VERSION 5.7 ;
  NOWIREEXTENSIONATPIN ON ;
  DIVIDERCHAR "/" ;
  BUSBITCHARS "[]" ;
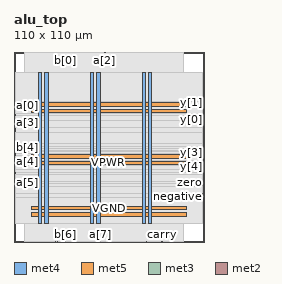
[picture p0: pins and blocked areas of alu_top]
MACRO alu_top
  CLASS BLOCK ;
  FOREIGN alu_top ;
  ORIGIN 0.000 0.000 ;
  SIZE 110.000 BY 110.000 ;
  PIN VGND
    DIRECTION INOUT ;
    USE GROUND ;
    PORT
      LAYER met4 ;
        RECT 17.820 10.640 19.820 98.160 ;
    END
    PORT
      LAYER met4 ;
        RECT 47.820 10.640 49.820 98.160 ;
    END
    PORT
      LAYER met4 ;
        RECT 77.820 10.640 79.820 98.160 ;
    END
    PORT
      LAYER met5 ;
        RECT 10.120 18.580 99.820 20.580 ;
    END
    PORT
      LAYER met5 ;
        RECT 10.120 48.580 99.820 50.580 ;
    END
    PORT
      LAYER met5 ;
        RECT 10.120 78.580 99.820 80.580 ;
    END
  END VGND
  PIN VPWR
    DIRECTION INOUT ;
    USE POWER ;
    PORT
      LAYER met4 ;
        RECT 14.120 10.640 16.120 98.160 ;
    END
    PORT
      LAYER met4 ;
        RECT 44.120 10.640 46.120 98.160 ;
    END
    PORT
      LAYER met4 ;
        RECT 74.120 10.640 76.120 98.160 ;
    END
    PORT
      LAYER met5 ;
        RECT 10.120 14.880 99.820 16.880 ;
    END
    PORT
      LAYER met5 ;
        RECT 10.120 44.880 99.820 46.880 ;
    END
    PORT
      LAYER met5 ;
        RECT 10.120 74.880 99.820 76.880 ;
    END
  END VPWR
  PIN a[0]
    DIRECTION INPUT ;
    USE SIGNAL ;
    ANTENNAGATEAREA 0.213000 ;
    PORT
      LAYER met3 ;
        RECT 0.000 78.920 0.600 79.520 ;
    END
  END a[0]
  PIN a[1]
    DIRECTION INPUT ;
    USE SIGNAL ;
    ANTENNAGATEAREA 0.213000 ;
    PORT
      LAYER met2 ;
        RECT 40.570 109.720 40.850 110.000 ;
    END
  END a[1]
  PIN a[2]
    DIRECTION INPUT ;
    USE SIGNAL ;
    ANTENNAGATEAREA 0.213000 ;
    PORT
      LAYER met2 ;
        RECT 52.530 109.720 52.810 110.000 ;
    END
  END a[2]
  PIN a[3]
    DIRECTION INPUT ;
    USE SIGNAL ;
    ANTENNAGATEAREA 0.213000 ;
    PORT
      LAYER met3 ;
        RECT 0.000 73.480 0.600 74.080 ;
    END
  END a[3]
  PIN a[4]
    DIRECTION INPUT ;
    USE SIGNAL ;
    ANTENNAGATEAREA 0.213000 ;
    PORT
      LAYER met3 ;
        RECT 0.000 46.280 0.600 46.880 ;
    END
  END a[4]
  PIN a[5]
    DIRECTION INPUT ;
    USE SIGNAL ;
    ANTENNAGATEAREA 0.213000 ;
    PORT
      LAYER met3 ;
        RECT 0.000 34.040 0.600 34.640 ;
    END
  END a[5]
  PIN a[6]
    DIRECTION INPUT ;
    USE SIGNAL ;
    ANTENNAGATEAREA 0.213000 ;
    PORT
      LAYER met2 ;
        RECT 28.610 0.000 28.890 0.280 ;
    END
  END a[6]
  PIN a[7]
    DIRECTION INPUT ;
    USE SIGNAL ;
    ANTENNAGATEAREA 0.213000 ;
    PORT
      LAYER met2 ;
        RECT 49.770 0.000 50.050 0.280 ;
    END
  END a[7]
  PIN b[0]
    DIRECTION INPUT ;
    USE SIGNAL ;
    ANTENNAGATEAREA 0.213000 ;
    PORT
      LAYER met2 ;
        RECT 29.530 109.720 29.810 110.000 ;
    END
  END b[0]
  PIN b[1]
    DIRECTION INPUT ;
    USE SIGNAL ;
    ANTENNAGATEAREA 0.213000 ;
    PORT
      LAYER met2 ;
        RECT 37.810 109.720 38.090 110.000 ;
    END
  END b[1]
  PIN b[2]
    DIRECTION INPUT ;
    USE SIGNAL ;
    ANTENNAGATEAREA 0.213000 ;
    PORT
      LAYER met2 ;
        RECT 55.290 109.720 55.570 110.000 ;
    END
  END b[2]
  PIN b[3]
    DIRECTION INPUT ;
    USE SIGNAL ;
    ANTENNAGATEAREA 0.213000 ;
    PORT
      LAYER met3 ;
        RECT 0.000 65.320 0.600 65.920 ;
    END
  END b[3]
  PIN b[4]
    DIRECTION INPUT ;
    USE SIGNAL ;
    ANTENNAGATEAREA 0.213000 ;
    PORT
      LAYER met3 ;
        RECT 0.000 50.360 0.600 50.960 ;
    END
  END b[4]
  PIN b[5]
    DIRECTION INPUT ;
    USE SIGNAL ;
    ANTENNAGATEAREA 0.213000 ;
    PORT
      LAYER met3 ;
        RECT 0.000 39.480 0.600 40.080 ;
    END
  END b[5]
  PIN b[6]
    DIRECTION INPUT ;
    USE SIGNAL ;
    ANTENNAGATEAREA 0.213000 ;
    PORT
      LAYER met2 ;
        RECT 29.530 0.000 29.810 0.280 ;
    END
  END b[6]
  PIN b[7]
    DIRECTION INPUT ;
    USE SIGNAL ;
    ANTENNAGATEAREA 0.213000 ;
    PORT
      LAYER met2 ;
        RECT 54.370 0.000 54.650 0.280 ;
    END
  END b[7]
  PIN carry
    DIRECTION OUTPUT ;
    USE SIGNAL ;
    ANTENNADIFFAREA 0.702900 ;
    PORT
      LAYER met2 ;
        RECT 85.650 0.000 85.930 0.280 ;
    END
  END carry
  PIN clk
    DIRECTION INPUT ;
    USE SIGNAL ;
    ANTENNAGATEAREA 0.852000 ;
    PORT
      LAYER met2 ;
        RECT 24.930 0.000 25.210 0.280 ;
    END
  END clk
  PIN negative
    DIRECTION OUTPUT ;
    USE SIGNAL ;
    ANTENNADIFFAREA 0.702900 ;
    PORT
      LAYER met3 ;
        RECT 109.400 25.880 110.000 26.480 ;
    END
  END negative
  PIN op[0]
    DIRECTION INPUT ;
    USE SIGNAL ;
    ANTENNAGATEAREA 0.213000 ;
    PORT
      LAYER met3 ;
        RECT 0.000 55.800 0.600 56.400 ;
    END
  END op[0]
  PIN op[1]
    DIRECTION INPUT ;
    USE SIGNAL ;
    ANTENNAGATEAREA 0.213000 ;
    PORT
      LAYER met3 ;
        RECT 0.000 63.960 0.600 64.560 ;
    END
  END op[1]
  PIN op[2]
    DIRECTION INPUT ;
    USE SIGNAL ;
    ANTENNAGATEAREA 0.213000 ;
    PORT
      LAYER met3 ;
        RECT 0.000 53.080 0.600 53.680 ;
    END
  END op[2]
  PIN overflow
    DIRECTION OUTPUT ;
    USE SIGNAL ;
    ANTENNADIFFAREA 0.702900 ;
    PORT
      LAYER met2 ;
        RECT 76.450 0.000 76.730 0.280 ;
    END
  END overflow
  PIN rst_n
    DIRECTION INPUT ;
    USE SIGNAL ;
    ANTENNAGATEAREA 0.213000 ;
    PORT
      LAYER met2 ;
        RECT 24.010 0.000 24.290 0.280 ;
    END
  END rst_n
  PIN y[0]
    DIRECTION OUTPUT ;
    USE SIGNAL ;
    ANTENNADIFFAREA 0.702900 ;
    PORT
      LAYER met3 ;
        RECT 109.400 70.760 110.000 71.360 ;
    END
  END y[0]
  PIN y[1]
    DIRECTION OUTPUT ;
    USE SIGNAL ;
    ANTENNADIFFAREA 0.702900 ;
    PORT
      LAYER met3 ;
        RECT 109.400 80.280 110.000 80.880 ;
    END
  END y[1]
  PIN y[2]
    DIRECTION OUTPUT ;
    USE SIGNAL ;
    ANTENNADIFFAREA 0.702900 ;
    PORT
      LAYER met3 ;
        RECT 109.400 72.120 110.000 72.720 ;
    END
  END y[2]
  PIN y[3]
    DIRECTION OUTPUT ;
    USE SIGNAL ;
    ANTENNADIFFAREA 0.702900 ;
    PORT
      LAYER met3 ;
        RECT 109.400 51.720 110.000 52.320 ;
    END
  END y[3]
  PIN y[4]
    DIRECTION OUTPUT ;
    USE SIGNAL ;
    ANTENNADIFFAREA 0.702900 ;
    PORT
      LAYER met3 ;
        RECT 109.400 43.560 110.000 44.160 ;
    END
  END y[4]
  PIN y[5]
    DIRECTION OUTPUT ;
    USE SIGNAL ;
    ANTENNADIFFAREA 0.702900 ;
    PORT
      LAYER met3 ;
        RECT 109.400 42.200 110.000 42.800 ;
    END
  END y[5]
  PIN y[6]
    DIRECTION OUTPUT ;
    USE SIGNAL ;
    ANTENNADIFFAREA 0.702900 ;
    PORT
      LAYER met3 ;
        RECT 109.400 32.680 110.000 33.280 ;
    END
  END y[6]
  PIN y[7]
    DIRECTION OUTPUT ;
    USE SIGNAL ;
    ANTENNADIFFAREA 0.702900 ;
    PORT
      LAYER met3 ;
        RECT 109.400 27.240 110.000 27.840 ;
    END
  END y[7]
  PIN zero
    DIRECTION OUTPUT ;
    USE SIGNAL ;
    ANTENNADIFFAREA 0.702900 ;
    PORT
      LAYER met3 ;
        RECT 109.400 34.040 110.000 34.640 ;
    END
  END zero
  OBS
      LAYER nwell ;
        RECT 9.930 10.795 100.010 98.005 ;
      LAYER li1 ;
        RECT 10.120 10.795 99.820 98.005 ;
      LAYER met1 ;
        RECT 6.050 10.640 99.820 98.160 ;
      LAYER met2 ;
        RECT 6.070 109.440 29.250 109.720 ;
        RECT 30.090 109.440 37.530 109.720 ;
        RECT 38.370 109.440 40.290 109.720 ;
        RECT 41.130 109.440 52.250 109.720 ;
        RECT 53.090 109.440 55.010 109.720 ;
        RECT 55.850 109.440 98.350 109.720 ;
        RECT 6.070 0.560 98.350 109.440 ;
        RECT 6.070 0.280 23.730 0.560 ;
        RECT 24.570 0.280 24.650 0.560 ;
        RECT 25.490 0.280 28.330 0.560 ;
        RECT 29.170 0.280 29.250 0.560 ;
        RECT 30.090 0.280 49.490 0.560 ;
        RECT 50.330 0.280 54.090 0.560 ;
        RECT 54.930 0.280 76.170 0.560 ;
        RECT 77.010 0.280 85.370 0.560 ;
        RECT 86.210 0.280 98.350 0.560 ;
      LAYER met3 ;
        RECT 0.600 81.280 109.400 98.085 ;
        RECT 0.600 79.920 109.000 81.280 ;
        RECT 1.000 79.880 109.000 79.920 ;
        RECT 1.000 78.520 109.400 79.880 ;
        RECT 0.600 74.480 109.400 78.520 ;
        RECT 1.000 73.120 109.400 74.480 ;
        RECT 1.000 73.080 109.000 73.120 ;
        RECT 0.600 70.360 109.000 73.080 ;
        RECT 0.600 66.320 109.400 70.360 ;
        RECT 1.000 63.560 109.400 66.320 ;
        RECT 0.600 56.800 109.400 63.560 ;
        RECT 1.000 55.400 109.400 56.800 ;
        RECT 0.600 54.080 109.400 55.400 ;
        RECT 1.000 52.720 109.400 54.080 ;
        RECT 1.000 52.680 109.000 52.720 ;
        RECT 0.600 51.360 109.000 52.680 ;
        RECT 1.000 51.320 109.000 51.360 ;
        RECT 1.000 49.960 109.400 51.320 ;
        RECT 0.600 47.280 109.400 49.960 ;
        RECT 1.000 45.880 109.400 47.280 ;
        RECT 0.600 44.560 109.400 45.880 ;
        RECT 0.600 41.800 109.000 44.560 ;
        RECT 0.600 40.480 109.400 41.800 ;
        RECT 1.000 39.080 109.400 40.480 ;
        RECT 0.600 35.040 109.400 39.080 ;
        RECT 1.000 33.640 109.000 35.040 ;
        RECT 0.600 32.280 109.000 33.640 ;
        RECT 0.600 28.240 109.400 32.280 ;
        RECT 0.600 25.480 109.000 28.240 ;
        RECT 0.600 10.715 109.400 25.480 ;
  END
END alu_top
END LIBRARY

